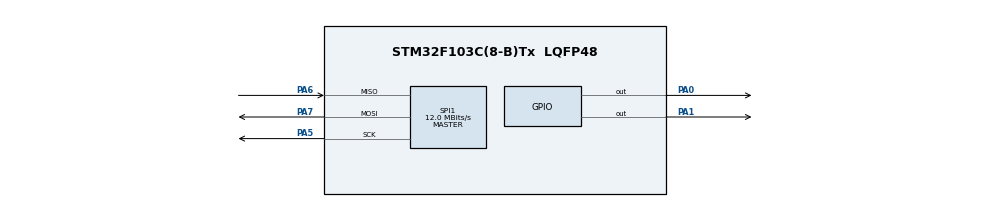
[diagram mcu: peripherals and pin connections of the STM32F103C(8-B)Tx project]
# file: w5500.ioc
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Mcu.Family=STM32F1
Mcu.Name=STM32F103C(8-B)Tx
Mcu.Package=LQFP48
NVIC.PriorityGroup=NVIC_PRIORITYGROUP_4
PA0-WKUP.Signal=GPIO_Output
PA1.Signal=GPIO_Output
PA13.Mode=Serial_Wire
PA13.Signal=SYS_JTMS-SWDIO
PA14.Mode=Serial_Wire
PA14.Signal=SYS_JTCK-SWCLK
PA5.Mode=Full_Duplex_Master
PA5.Signal=SPI1_SCK
PA6.Mode=Full_Duplex_Master
PA6.Signal=SPI1_MISO
PA7.Mode=Full_Duplex_Master
PA7.Signal=SPI1_MOSI
PD0-OSC_IN.Mode=HSE-External-Oscillator
PD0-OSC_IN.Signal=RCC_OSC_IN
PD1-OSC_OUT.Mode=HSE-External-Oscillator
PD1-OSC_OUT.Signal=RCC_OSC_OUT
ProjectManager.HeapSize=0x200
ProjectManager.StackSize=0x400
ProjectManager.TargetToolchain=STM32CubeIDE
RCC.AHBFreq_Value=48000000
RCC.APB1Freq_Value=48000000
RCC.APB1TimFreq_Value=48000000
RCC.APB2Freq_Value=48000000
RCC.APB2TimFreq_Value=48000000
RCC.HCLKFreq_Value=48000000
RCC.PLLMUL=RCC_PLL_MUL6
RCC.PLLSourceVirtual=RCC_PLLSOURCE_HSE
RCC.SYSCLKFreq_VALUE=48000000
RCC.SYSCLKSource=RCC_SYSCLKSOURCE_PLLCLK
RCC.USBFreq_Value=48000000
SPI1.BaudRatePrescaler=SPI_BAUDRATEPRESCALER_4
SPI1.CalculateBaudRate=12.0 MBits/s
SPI1.Direction=SPI_DIRECTION_2LINES
SPI1.Mode=SPI_MODE_MASTER
SPI1.VirtualType=VM_MASTER
board=custom

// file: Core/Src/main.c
/* USER CODE BEGIN Header */
/**
  ******************************************************************************
  * @file           : main.c
  * @brief          : Main program body
  ******************************************************************************
  * @attention
  *
  * Copyright (c) 2024 STMicroelectronics.
  * All rights reserved.
  *
  * This software is licensed under terms that can be found in the LICENSE file
  * in the root directory of this software component.
  * If no LICENSE file comes with this software, it is provided AS-IS.
  *
  ******************************************************************************
  */
/* USER CODE END Header */
#include "main.h"
#include "spi.h"
#include "gpio.h"
#include "wizchip_conf.h"
#include "W5500_SPI.h"
#include "socket.h"

void SystemClock_Config(void);

int main(void)
{

  /* MCU Configuration--------------------------------------------------------*/

  /* Reset of all peripherals, Initializes the Flash interface and the Systick. */
  HAL_Init();

  /* Configure the system clock */
  SystemClock_Config();

  /* Initialize all configured peripherals */
  MX_GPIO_Init();
  MX_SPI1_Init();

  /* Infinite loop */
  while (1)
  {

  }
}

void SystemClock_Config(void)
{
  RCC_OscInitTypeDef RCC_OscInitStruct = {0};
  RCC_ClkInitTypeDef RCC_ClkInitStruct = {0};

  /** Initializes the RCC Oscillators according to the specified parameters
  * in the RCC_OscInitTypeDef structure.
  */
  RCC_OscInitStruct.OscillatorType = RCC_OSCILLATORTYPE_HSE;
  RCC_OscInitStruct.HSEState = RCC_HSE_ON;
  RCC_OscInitStruct.HSEPredivValue = RCC_HSE_PREDIV_DIV1;
  RCC_OscInitStruct.HSIState = RCC_HSI_ON;
  RCC_OscInitStruct.PLL.PLLState = RCC_PLL_ON;
  RCC_OscInitStruct.PLL.PLLSource = RCC_PLLSOURCE_HSE;
  RCC_OscInitStruct.PLL.PLLMUL = RCC_PLL_MUL6;
  if (HAL_RCC_OscConfig(&RCC_OscInitStruct) != HAL_OK)
  {
    Error_Handler();
  }

  /** Initializes the CPU, AHB and APB buses clocks
  */
  RCC_ClkInitStruct.ClockType = RCC_CLOCKTYPE_HCLK|RCC_CLOCKTYPE_SYSCLK
                              |RCC_CLOCKTYPE_PCLK1|RCC_CLOCKTYPE_PCLK2;
  RCC_ClkInitStruct.SYSCLKSource = RCC_SYSCLKSOURCE_PLLCLK;
  RCC_ClkInitStruct.AHBCLKDivider = RCC_SYSCLK_DIV1;
  RCC_ClkInitStruct.APB1CLKDivider = RCC_HCLK_DIV2;
  RCC_ClkInitStruct.APB2CLKDivider = RCC_HCLK_DIV1;

  if (HAL_RCC_ClockConfig(&RCC_ClkInitStruct, FLASH_LATENCY_1) != HAL_OK)
  {
    Error_Handler();
  }
}

void Error_Handler(void)
{
  __disable_irq();
  while (1)
  {
  }
}
